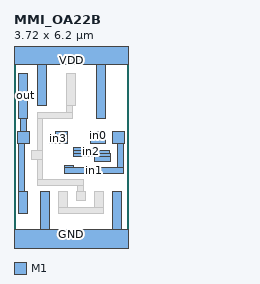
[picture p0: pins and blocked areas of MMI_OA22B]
MACRO MMI_OA22B
	CLASS CORE ;
	FOREIGN MMI_OA22B 0 0 ;
	SIZE 3.72 BY 6.2 ;
	SYMMETRY X Y ;
	SITE CORE1 ;
	PIN out
		DIRECTION output ;
		USE SIGNAL ;
		PORT
			LAYER M1 ;
			RECT 0.16 4.03 0.44 5.5 ;
			LAYER M1 ;
			RECT 0.2 3.6 0.395 4.03 ;
			LAYER M1 ;
			RECT 0.12 3.22 0.5 3.6 ;
			LAYER M1 ;
			RECT 0.16 1.64 0.355 3.22 ;
			LAYER M1 ;
			RECT 0.16 0.94 0.44 1.64 ;
		END
		AntennaDiffArea 0.91245 ;
	END out
	PIN in1
		DIRECTION input ;
		USE SIGNAL ;
		PORT
			LAYER M1 ;
			RECT 3.26 3.6 3.575 3.61 ;
			LAYER M1 ;
			RECT 3.22 3.22 3.6 3.6 ;
			LAYER M1 ;
			RECT 1.65 2.42 1.93 2.51 ;
			LAYER M1 ;
			RECT 3.375 2.42 3.565 3.22 ;
			LAYER M1 ;
			RECT 1.65 2.23 3.565 2.42 ;
		END
		AntennaGateArea 0.3465 ;
	END in1
	PIN GND
		DIRECTION inout ;
		USE GROUND ;
		PORT
			LAYER M1 ;
			RECT 0.865 0.42 1.145 1.64 ;
			LAYER M1 ;
			RECT 3.225 0.42 3.505 1.64 ;
			LAYER M1 ;
			RECT 0 -0.42 3.72 0.42 ;
		END
	END GND
	PIN in2
		DIRECTION input ;
		USE SIGNAL ;
		PORT
			LAYER M1 ;
			RECT 1.94 3 2.22 3.08 ;
			LAYER M1 ;
			RECT 1.94 2.9 3.11 3 ;
			LAYER M1 ;
			RECT 1.94 2.805 3.165 2.9 ;
			LAYER M1 ;
			RECT 1.94 2.8 2.22 2.805 ;
			LAYER M1 ;
			RECT 2.615 2.625 3.165 2.805 ;
			LAYER M1 ;
			RECT 2.885 2.62 3.165 2.625 ;
		END
		AntennaGateArea 0.3465 ;
	END in2
	PIN VDD
		DIRECTION inout ;
		USE POWER ;
		PORT
			LAYER M1 ;
			RECT 0 5.78 3.72 6.62 ;
			LAYER M1 ;
			RECT 0.765 4.44 1.045 5.78 ;
			LAYER M1 ;
			RECT 2.7 4.03 2.98 5.78 ;
		END
	END VDD
	PIN in3
		DIRECTION input ;
		USE SIGNAL ;
		PORT
			LAYER M1 ;
			RECT 1.36 3.505 1.74 3.6 ;
			LAYER M1 ;
			RECT 1.16 3.225 1.74 3.505 ;
			LAYER M1 ;
			RECT 1.36 3.22 1.74 3.225 ;
		END
		AntennaGateArea 0.3465 ;
	END in3
	PIN in0
		DIRECTION input ;
		USE SIGNAL ;
		PORT
			LAYER M1 ;
			RECT 2.6 3.505 2.98 3.6 ;
			LAYER M1 ;
			RECT 2.51 3.225 2.98 3.505 ;
			LAYER M1 ;
			RECT 2.6 3.22 2.98 3.225 ;
		END
		AntennaGateArea 0.3465 ;
	END in0
	OBS
		LAYER M1 ;
		RECT 1.725 4.44 2.005 5.5 ;
		LAYER M1 ;
		RECT 1.725 4.225 1.92 4.44 ;
		LAYER M1 ;
		RECT 0.755 4.03 1.92 4.225 ;
		LAYER M1 ;
		RECT 0.755 2.97 0.945 4.03 ;
		LAYER M1 ;
		RECT 0.565 2.69 0.945 2.97 ;
		LAYER M1 ;
		RECT 0.755 2.03 0.945 2.69 ;
		LAYER M1 ;
		RECT 0.755 1.84 2.255 2.03 ;
		LAYER M1 ;
		RECT 2.06 1.64 2.255 1.84 ;
		LAYER M1 ;
		RECT 1.455 1.13 1.735 1.64 ;
		LAYER M1 ;
		RECT 2.045 1.36 2.325 1.64 ;
		LAYER M1 ;
		RECT 2.635 1.13 2.915 1.64 ;
		LAYER M1 ;
		RECT 1.455 0.94 2.915 1.13 ;
	END
END MMI_OA22B
